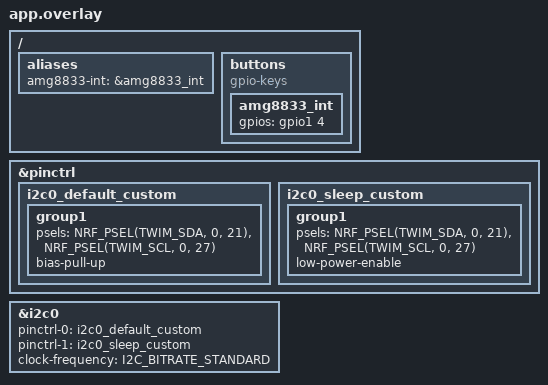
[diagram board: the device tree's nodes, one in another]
/ {
    aliases {
        amg8833-int = &amg8833_int;
    };

    buttons {
        compatible = "gpio-keys";

        amg8833_int: amg8833_int {
            gpios = <&gpio1 4 GPIO_ACTIVE_HIGH>;
        };
    };
};

&pinctrl {
    i2c0_default_custom: i2c0_default_custom {
        group1 {
            psels = <NRF_PSEL(TWIM_SDA, 0, 21)>,
                    <NRF_PSEL(TWIM_SCL, 0, 27)>;
            bias-pull-up;
        };
    };

    i2c0_sleep_custom: i2c0_sleep_custom {
        group1 {
            psels = <NRF_PSEL(TWIM_SDA, 0, 21)>,
                    <NRF_PSEL(TWIM_SCL, 0, 27)>;
            low-power-enable;
        };
    };
};

&i2c0 {
    status = "okay";
    pinctrl-0 = <&i2c0_default_custom>;
    pinctrl-1 = <&i2c0_sleep_custom>;
    pinctrl-names = "default", "sleep";
    clock-frequency = <I2C_BITRATE_STANDARD>;
};
